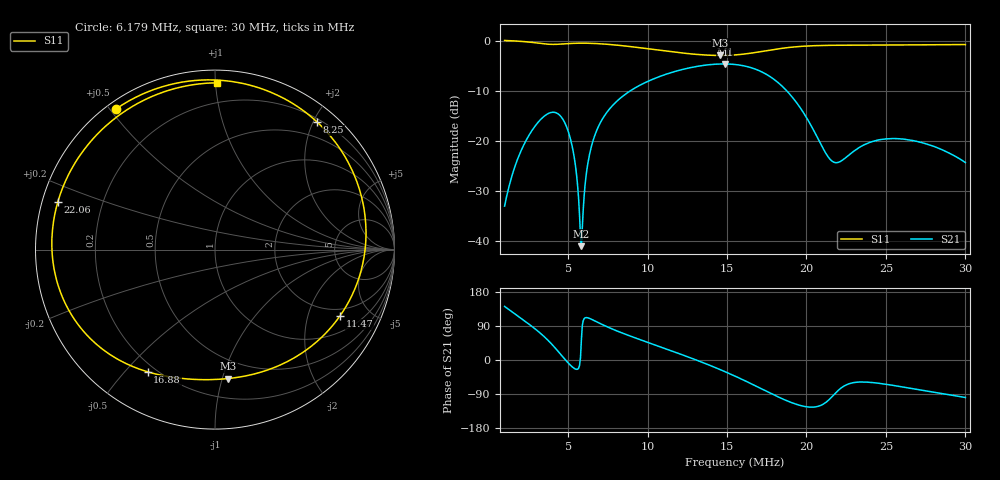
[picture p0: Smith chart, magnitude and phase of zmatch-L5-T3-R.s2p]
# HZ S RI R 50
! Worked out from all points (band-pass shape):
!   505 points, 1 MHz to 30 MHz, reference 50 ohm
!   highest |S21| = -4.53 dB at 14.87 MHz (marker M1); lowest = -41.1 dB at 5.833 MHz (marker M2)
!   |S21| within 3 dB of the highest: 10.37 MHz to 17.92 MHz (7.543 MHz wide, 53.3 % of centre)
!   lowest |S11| = -2.8 dB at 14.58 MHz (marker M3), VSWR 6.20, Z = 17.4 - j52.3 ohm
!   |S11| at or under -10 dB: nowhere
!   S12 and S22 are empty: the file has one direction only
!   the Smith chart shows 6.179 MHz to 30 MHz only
!   S11 on the Smith chart (normalised r, x): 6.179 MHz: 0.03, +0.52; 8.25 MHz: 0.25, +2.05; 11.47 MHz: 1.65, -3.23; 16.88 MHz: 0.17, -0.58; 22.06 MHz: 0.05, +0.15; 30 MHz: 0.07, +1.01
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1000000  -0.6218 0.8101  -0.0174 0.0139  0 0  0 0
2150800  0.3328 0.9396  -0.0246 0.0842  0 0  0 0
3128980  0.9579 0.047  0.0404 0.1505  0 0  0 0
3589300  0.732 -0.5906  0.0972 0.1545  0 0  0 0
4164700  -0.0942 -0.9281  0.1632 0.1045  0 0  0 0
4912720  -0.8968 -0.3061  0.1372 -0.009  0 0  0 0
5430580  -0.9198 0.2633  0.0561 -0.0241  0 0  0 0
5833360  -0.7537 0.5933  0.00517 0.00716  0 0  0 0
6178600  -0.5527 0.7828  -0.0193 0.0481  0 0  0 0
7099240  0.0252 0.9437  -0.0125 0.1602  0 0  0 0
8250040  0.5682 0.7113  0.075 0.2559  0 0  0 0
9400840  0.8164 0.2939  0.2005 0.2929  0 0  0 0
1.066672e7  0.8045 -0.1498  0.3526 0.2611  0 0  0 0
1.147228e7  0.6962 -0.3697  0.4419 0.2014  0 0  0 0
1.457944e7  0.0739 -0.7183  0.5351 -0.256  0 0  0 0
1.486714e7  0.0176 -0.7228  0.5104 -0.3035  0 0  0 0
1.550008e7  -0.104 -0.7237  0.432 -0.3961  0 0  0 0
1.688104e7  -0.3751 -0.6809  0.1771 -0.4882  0 0  0 0
2.033344e7  -0.897 -0.1057  -0.0785 -0.1145  0 0  0 0
2.205964e7  -0.8759 0.2654  0.0129 -0.0603  0 0  0 0
2.51668e7  -0.5789 0.7141  0.0445 -0.0958  0 0  0 0
3.000016e7  0.0115 0.9291  -0.00955 -0.0602  0 0  0 0
